VERSION 5.4 ;
NAMESCASESENSITIVE ON ;
BUSBITCHARS "[]" ;
DIVIDERCHAR "/" ;
UNITS
  DATABASE MICRONS 2000 ;
END UNITS
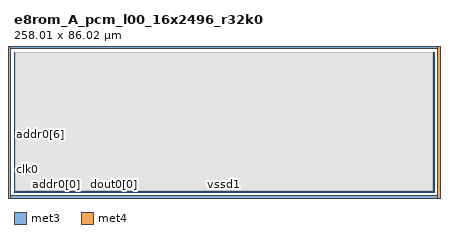
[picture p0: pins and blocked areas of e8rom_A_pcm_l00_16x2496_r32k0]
MACRO e8rom_A_pcm_l00_16x2496_r32k0
   CLASS BLOCK ;
   SIZE 258.01 BY 86.02 ;
   SYMMETRY X Y R90 ;
   PIN clk0
      DIRECTION INPUT ;
      PORT
         LAYER met3 ;
         RECT  -7.48 8.99 -7.1 9.37 ;
      END
   END clk0
   PIN cs0
      DIRECTION INPUT ;
      PORT
         LAYER met4 ;
         RECT  8.545 -7.48 8.925 -7.1 ;
      END
   END cs0
   PIN addr0[0]
      DIRECTION INPUT ;
      PORT
         LAYER met4 ;
         RECT  26.11 -7.48 26.49 -7.1 ;
      END
   END addr0[0]
   PIN addr0[1]
      DIRECTION INPUT ;
      PORT
         LAYER met4 ;
         RECT  28.15 -7.48 28.53 -7.1 ;
      END
   END addr0[1]
   PIN addr0[2]
      DIRECTION INPUT ;
      PORT
         LAYER met4 ;
         RECT  30.19 -7.48 30.57 -7.1 ;
      END
   END addr0[2]
   PIN addr0[3]
      DIRECTION INPUT ;
      PORT
         LAYER met4 ;
         RECT  32.23 -7.48 32.61 -7.1 ;
      END
   END addr0[3]
   PIN addr0[4]
      DIRECTION INPUT ;
      PORT
         LAYER met3 ;
         RECT  -7.48 33.89 -7.1 34.27 ;
      END
   END addr0[4]
   PIN addr0[5]
      DIRECTION INPUT ;
      PORT
         LAYER met3 ;
         RECT  -7.48 34.635 -7.1 35.015 ;
      END
   END addr0[5]
   PIN addr0[6]
      DIRECTION INPUT ;
      PORT
         LAYER met3 ;
         RECT  -7.48 35.325 -7.1 35.705 ;
      END
   END addr0[6]
   PIN addr0[7]
      DIRECTION INPUT ;
      PORT
         LAYER met3 ;
         RECT  -7.48 32.42 -7.1 32.8 ;
      END
   END addr0[7]
   PIN addr0[8]
      DIRECTION INPUT ;
      PORT
         LAYER met3 ;
         RECT  -7.48 36.015 -7.1 36.395 ;
      END
   END addr0[8]
   PIN dout0[0]
      DIRECTION OUTPUT ;
      PORT
         LAYER met4 ;
         RECT  61.115 -7.48 61.495 -7.1 ;
      END
   END dout0[0]
   PIN dout0[1]
      DIRECTION OUTPUT ;
      PORT
         LAYER met4 ;
         RECT  62.655 -7.48 63.035 -7.1 ;
      END
   END dout0[1]
   PIN dout0[2]
      DIRECTION OUTPUT ;
      PORT
         LAYER met4 ;
         RECT  64.195 -7.48 64.575 -7.1 ;
      END
   END dout0[2]
   PIN dout0[3]
      DIRECTION OUTPUT ;
      PORT
         LAYER met4 ;
         RECT  65.735 -7.48 66.115 -7.1 ;
      END
   END dout0[3]
   PIN dout0[4]
      DIRECTION OUTPUT ;
      PORT
         LAYER met4 ;
         RECT  67.275 -7.48 67.655 -7.1 ;
      END
   END dout0[4]
   PIN dout0[5]
      DIRECTION OUTPUT ;
      PORT
         LAYER met4 ;
         RECT  68.815 -7.48 69.195 -7.1 ;
      END
   END dout0[5]
   PIN dout0[6]
      DIRECTION OUTPUT ;
      PORT
         LAYER met4 ;
         RECT  70.355 -7.48 70.735 -7.1 ;
      END
   END dout0[6]
   PIN dout0[7]
      DIRECTION OUTPUT ;
      PORT
         LAYER met4 ;
         RECT  71.895 -7.48 72.275 -7.1 ;
      END
   END dout0[7]
   PIN dout0[8]
      DIRECTION OUTPUT ;
      PORT
         LAYER met4 ;
         RECT  73.435 -7.48 73.815 -7.1 ;
      END
   END dout0[8]
   PIN dout0[9]
      DIRECTION OUTPUT ;
      PORT
         LAYER met4 ;
         RECT  74.975 -7.48 75.355 -7.1 ;
      END
   END dout0[9]
   PIN dout0[10]
      DIRECTION OUTPUT ;
      PORT
         LAYER met4 ;
         RECT  76.515 -7.48 76.895 -7.1 ;
      END
   END dout0[10]
   PIN dout0[11]
      DIRECTION OUTPUT ;
      PORT
         LAYER met4 ;
         RECT  78.055 -7.48 78.435 -7.1 ;
      END
   END dout0[11]
   PIN dout0[12]
      DIRECTION OUTPUT ;
      PORT
         LAYER met4 ;
         RECT  79.595 -7.48 79.975 -7.1 ;
      END
   END dout0[12]
   PIN dout0[13]
      DIRECTION OUTPUT ;
      PORT
         LAYER met4 ;
         RECT  81.135 -7.48 81.515 -7.1 ;
      END
   END dout0[13]
   PIN dout0[14]
      DIRECTION OUTPUT ;
      PORT
         LAYER met4 ;
         RECT  82.675 -7.48 83.055 -7.1 ;
      END
   END dout0[14]
   PIN dout0[15]
      DIRECTION OUTPUT ;
      PORT
         LAYER met4 ;
         RECT  84.215 -7.48 84.595 -7.1 ;
      END
   END dout0[15]
   PIN vccd1
      DIRECTION INOUT ;
      USE POWER ; 
      SHAPE ABUTMENT ; 
      PORT
         LAYER met3 ;
         RECT  -7.48 91.76 265.49 93.5 ;
         LAYER met4 ;
         RECT  263.75 -7.48 265.49 93.5 ;
         LAYER met4 ;
         RECT  -7.48 -7.48 -5.74 93.5 ;
         LAYER met3 ;
         RECT  -7.48 -7.48 265.49 -5.74 ;
      END
   END vccd1
   PIN vssd1
      DIRECTION INOUT ;
      USE GROUND ; 
      SHAPE ABUTMENT ; 
      PORT
         LAYER met4 ;
         RECT  -4.0 -4.0 -2.26 90.02 ;
         LAYER met4 ;
         RECT  260.27 -4.0 262.01 90.02 ;
         LAYER met3 ;
         RECT  -4.0 88.28 262.01 90.02 ;
         LAYER met3 ;
         RECT  -4.0 -4.0 262.01 -2.26 ;
      END
   END vssd1
   OBS
   LAYER  met1 ;
      RECT  0.62 0.62 257.39 85.4 ;
   LAYER  met2 ;
      RECT  0.62 0.62 257.39 85.4 ;
   LAYER  met3 ;
      RECT  0.62 0.62 257.39 85.4 ;
   LAYER  met4 ;
      RECT  0.62 0.62 257.39 85.4 ;
   END
END    e8rom_A_pcm_l00_16x2496_r32k0
END    LIBRARY
